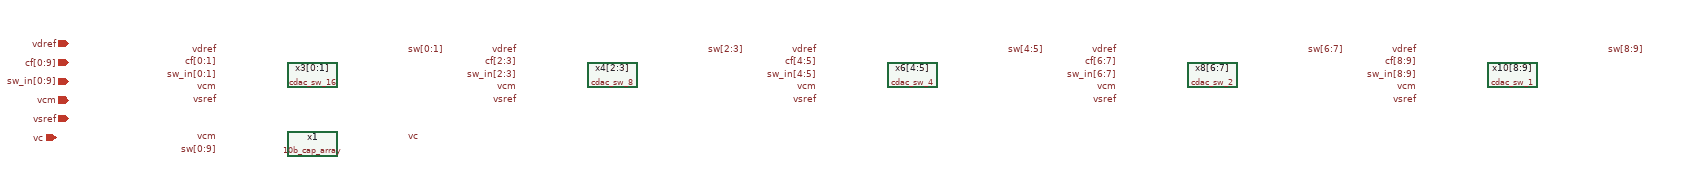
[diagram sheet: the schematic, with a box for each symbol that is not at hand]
v {xschem version=3.4.5 file_version=1.2
}
G {}
K {}
V {}
S {}
E {}
C {10b_cap_array.sym} 570 -460 0 0 {name=x1}
C {cdac_sw_16.sym} 570 -570 0 0 {name=x3[0:1]}
C {devices/lab_wire.sym} 420 -610 0 0 {name=p1 sig_type=std_logic lab=vdref}
C {devices/lab_wire.sym} 420 -530 0 0 {name=p3 sig_type=std_logic lab=vsref}
C {devices/lab_wire.sym} 720 -610 2 0 {name=p5 sig_type=std_logic lab=sw[0:1]}
C {devices/lab_wire.sym} 420 -450 0 0 {name=p6 sig_type=std_logic lab=sw[0:9]}
C {devices/lab_wire.sym} 420 -470 0 0 {name=p9 sig_type=std_logic lab=vcm}
C {devices/lab_wire.sym} 420 -550 0 0 {name=p11 sig_type=std_logic lab=vcm}
C {devices/lab_wire.sym} 420 -590 0 0 {name=p12 sig_type=std_logic lab=cf[0:1]}
C {devices/lab_wire.sym} 420 -570 0 0 {name=p14 sig_type=std_logic lab=sw_in[0:1]}
C {devices/lab_wire.sym} 720 -470 0 1 {name=p16 sig_type=std_logic lab=vc}
C {devices/ipin.sym} 180 -620 0 0 {name=p18 lab=vdref}
C {devices/ipin.sym} 180 -590 0 0 {name=p19 lab=cf[0:9]}
C {devices/ipin.sym} 180 -560 0 0 {name=p20 lab=sw_in[0:9]}
C {devices/ipin.sym} 180 -530 0 0 {name=p22 lab=vcm}
C {devices/ipin.sym} 180 -500 0 0 {name=p23 lab=vsref}
C {devices/iopin.sym} 160 -470 0 0 {name=p24 lab=vc}
C {cdac_sw_8.sym} 1050 -570 0 0 {name=x4[2:3]}
C {devices/lab_wire.sym} 900 -610 0 0 {name=p26 sig_type=std_logic lab=vdref}
C {devices/lab_wire.sym} 900 -530 0 0 {name=p29 sig_type=std_logic lab=vsref}
C {devices/lab_wire.sym} 1200 -610 2 0 {name=p31 sig_type=std_logic lab=sw[2:3]}
C {devices/lab_wire.sym} 900 -550 0 0 {name=p34 sig_type=std_logic lab=vcm}
C {devices/lab_wire.sym} 900 -590 0 0 {name=p35 sig_type=std_logic lab=cf[2:3]}
C {devices/lab_wire.sym} 900 -570 0 0 {name=p37 sig_type=std_logic lab=sw_in[2:3]}
C {cdac_sw_4.sym} 1530 -570 0 0 {name=x6[4:5]}
C {devices/lab_wire.sym} 1380 -610 0 0 {name=p39 sig_type=std_logic lab=vdref}
C {devices/lab_wire.sym} 1380 -530 0 0 {name=p41 sig_type=std_logic lab=vsref}
C {devices/lab_wire.sym} 1680 -610 2 0 {name=p43 sig_type=std_logic lab=sw[4:5]}
C {devices/lab_wire.sym} 1380 -550 0 0 {name=p46 sig_type=std_logic lab=vcm}
C {devices/lab_wire.sym} 1380 -590 0 0 {name=p47 sig_type=std_logic lab=cf[4:5]}
C {devices/lab_wire.sym} 1380 -570 0 0 {name=p49 sig_type=std_logic lab=sw_in[4:5]}
C {cdac_sw_2.sym} 2010 -570 0 0 {name=x8[6:7]}
C {devices/lab_wire.sym} 1860 -610 0 0 {name=p51 sig_type=std_logic lab=vdref}
C {devices/lab_wire.sym} 1860 -530 0 0 {name=p53 sig_type=std_logic lab=vsref}
C {devices/lab_wire.sym} 2160 -610 2 0 {name=p55 sig_type=std_logic lab=sw[6:7]}
C {devices/lab_wire.sym} 1860 -550 0 0 {name=p58 sig_type=std_logic lab=vcm}
C {devices/lab_wire.sym} 1860 -590 0 0 {name=p59 sig_type=std_logic lab=cf[6:7]}
C {devices/lab_wire.sym} 1860 -570 0 0 {name=p61 sig_type=std_logic lab=sw_in[6:7]}
C {cdac_sw_1.sym} 2490 -570 0 0 {name=x10[8:9]}
C {devices/lab_wire.sym} 2340 -610 0 0 {name=p63 sig_type=std_logic lab=vdref}
C {devices/lab_wire.sym} 2340 -530 0 0 {name=p65 sig_type=std_logic lab=vsref}
C {devices/lab_wire.sym} 2640 -610 2 0 {name=p67 sig_type=std_logic lab=sw[8:9]}
C {devices/lab_wire.sym} 2340 -550 0 0 {name=p70 sig_type=std_logic lab=vcm}
C {devices/lab_wire.sym} 2340 -590 0 0 {name=p71 sig_type=std_logic lab=cf[8:9]}
C {devices/lab_wire.sym} 2340 -570 0 0 {name=p73 sig_type=std_logic lab=sw_in[8:9]}
